# Generated by FakeRAM 2.0
VERSION 5.7 ;
BUSBITCHARS "[]" ;
PROPERTYDEFINITIONS
  MACRO width INTEGER ;
  MACRO depth INTEGER ;
  MACRO banks INTEGER ;
END PROPERTYDEFINITIONS
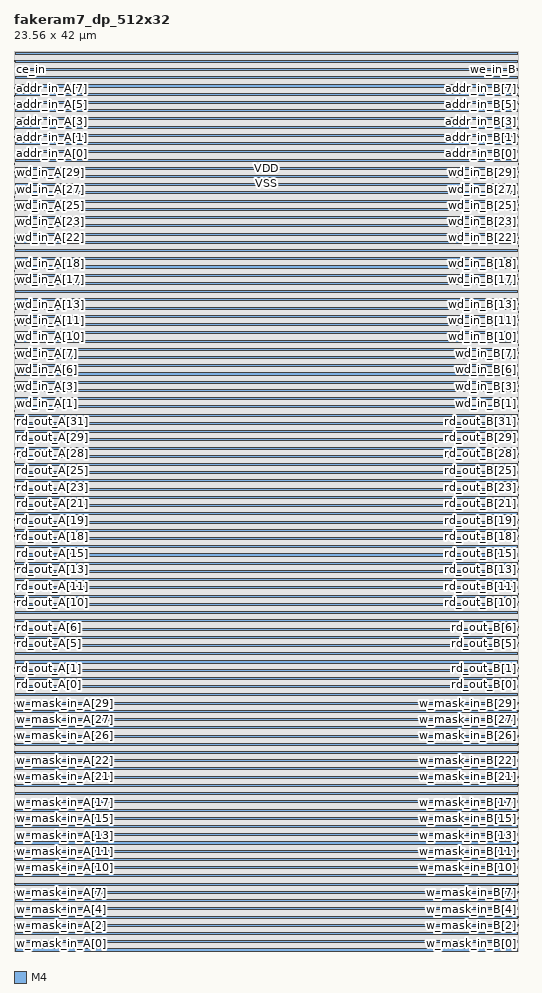
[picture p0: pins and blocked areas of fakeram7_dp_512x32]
MACRO fakeram7_dp_512x32
  PROPERTY width 32 ;
  PROPERTY depth 512 ;
  PROPERTY banks 4 ;
  FOREIGN fakeram7_dp_512x32 0 0 ;
  SYMMETRY X Y ;
  SIZE 23.560 BY 42.000 ;
  CLASS BLOCK ;
  PIN w_mask_in_A[0]
    DIRECTION INPUT ;
    USE SIGNAL ;
    SHAPE ABUTMENT ;
    PORT
      LAYER M4 ;
      RECT 0.000 0.048 0.024 0.072 ;
    END
  END w_mask_in_A[0]
  PIN w_mask_in_B[0]
    DIRECTION INPUT ;
    USE SIGNAL ;
    SHAPE ABUTMENT ;
    PORT
      LAYER M4 ;
      RECT 23.536 0.048 23.560 0.072 ;
    END
  END w_mask_in_B[0]
  PIN w_mask_in_A[1]
    DIRECTION INPUT ;
    USE SIGNAL ;
    SHAPE ABUTMENT ;
    PORT
      LAYER M4 ;
      RECT 0.000 0.432 0.024 0.456 ;
    END
  END w_mask_in_A[1]
  PIN w_mask_in_B[1]
    DIRECTION INPUT ;
    USE SIGNAL ;
    SHAPE ABUTMENT ;
    PORT
      LAYER M4 ;
      RECT 23.536 0.432 23.560 0.456 ;
    END
  END w_mask_in_B[1]
  PIN w_mask_in_A[2]
    DIRECTION INPUT ;
    USE SIGNAL ;
    SHAPE ABUTMENT ;
    PORT
      LAYER M4 ;
      RECT 0.000 0.816 0.024 0.840 ;
    END
  END w_mask_in_A[2]
  PIN w_mask_in_B[2]
    DIRECTION INPUT ;
    USE SIGNAL ;
    SHAPE ABUTMENT ;
    PORT
      LAYER M4 ;
      RECT 23.536 0.816 23.560 0.840 ;
    END
  END w_mask_in_B[2]
  PIN w_mask_in_A[3]
    DIRECTION INPUT ;
    USE SIGNAL ;
    SHAPE ABUTMENT ;
    PORT
      LAYER M4 ;
      RECT 0.000 1.200 0.024 1.224 ;
    END
  END w_mask_in_A[3]
  PIN w_mask_in_B[3]
    DIRECTION INPUT ;
    USE SIGNAL ;
    SHAPE ABUTMENT ;
    PORT
      LAYER M4 ;
      RECT 23.536 1.200 23.560 1.224 ;
    END
  END w_mask_in_B[3]
  PIN w_mask_in_A[4]
    DIRECTION INPUT ;
    USE SIGNAL ;
    SHAPE ABUTMENT ;
    PORT
      LAYER M4 ;
      RECT 0.000 1.584 0.024 1.608 ;
    END
  END w_mask_in_A[4]
  PIN w_mask_in_B[4]
    DIRECTION INPUT ;
    USE SIGNAL ;
    SHAPE ABUTMENT ;
    PORT
      LAYER M4 ;
      RECT 23.536 1.584 23.560 1.608 ;
    END
  END w_mask_in_B[4]
  PIN w_mask_in_A[5]
    DIRECTION INPUT ;
    USE SIGNAL ;
    SHAPE ABUTMENT ;
    PORT
      LAYER M4 ;
      RECT 0.000 1.968 0.024 1.992 ;
    END
  END w_mask_in_A[5]
  PIN w_mask_in_B[5]
    DIRECTION INPUT ;
    USE SIGNAL ;
    SHAPE ABUTMENT ;
    PORT
      LAYER M4 ;
      RECT 23.536 1.968 23.560 1.992 ;
    END
  END w_mask_in_B[5]
  PIN w_mask_in_A[6]
    DIRECTION INPUT ;
    USE SIGNAL ;
    SHAPE ABUTMENT ;
    PORT
      LAYER M4 ;
      RECT 0.000 2.352 0.024 2.376 ;
    END
  END w_mask_in_A[6]
  PIN w_mask_in_B[6]
    DIRECTION INPUT ;
    USE SIGNAL ;
    SHAPE ABUTMENT ;
    PORT
      LAYER M4 ;
      RECT 23.536 2.352 23.560 2.376 ;
    END
  END w_mask_in_B[6]
  PIN w_mask_in_A[7]
    DIRECTION INPUT ;
    USE SIGNAL ;
    SHAPE ABUTMENT ;
    PORT
      LAYER M4 ;
      RECT 0.000 2.736 0.024 2.760 ;
    END
  END w_mask_in_A[7]
  PIN w_mask_in_B[7]
    DIRECTION INPUT ;
    USE SIGNAL ;
    SHAPE ABUTMENT ;
    PORT
      LAYER M4 ;
      RECT 23.536 2.736 23.560 2.760 ;
    END
  END w_mask_in_B[7]
  PIN w_mask_in_A[8]
    DIRECTION INPUT ;
    USE SIGNAL ;
    SHAPE ABUTMENT ;
    PORT
      LAYER M4 ;
      RECT 0.000 3.120 0.024 3.144 ;
    END
  END w_mask_in_A[8]
  PIN w_mask_in_B[8]
    DIRECTION INPUT ;
    USE SIGNAL ;
    SHAPE ABUTMENT ;
    PORT
      LAYER M4 ;
      RECT 23.536 3.120 23.560 3.144 ;
    END
  END w_mask_in_B[8]
  PIN w_mask_in_A[9]
    DIRECTION INPUT ;
    USE SIGNAL ;
    SHAPE ABUTMENT ;
    PORT
      LAYER M4 ;
      RECT 0.000 3.504 0.024 3.528 ;
    END
  END w_mask_in_A[9]
  PIN w_mask_in_B[9]
    DIRECTION INPUT ;
    USE SIGNAL ;
    SHAPE ABUTMENT ;
    PORT
      LAYER M4 ;
      RECT 23.536 3.504 23.560 3.528 ;
    END
  END w_mask_in_B[9]
  PIN w_mask_in_A[10]
    DIRECTION INPUT ;
    USE SIGNAL ;
    SHAPE ABUTMENT ;
    PORT
      LAYER M4 ;
      RECT 0.000 3.888 0.024 3.912 ;
    END
  END w_mask_in_A[10]
  PIN w_mask_in_B[10]
    DIRECTION INPUT ;
    USE SIGNAL ;
    SHAPE ABUTMENT ;
    PORT
      LAYER M4 ;
      RECT 23.536 3.888 23.560 3.912 ;
    END
  END w_mask_in_B[10]
  PIN w_mask_in_A[11]
    DIRECTION INPUT ;
    USE SIGNAL ;
    SHAPE ABUTMENT ;
    PORT
      LAYER M4 ;
      RECT 0.000 4.272 0.024 4.296 ;
    END
  END w_mask_in_A[11]
  PIN w_mask_in_B[11]
    DIRECTION INPUT ;
    USE SIGNAL ;
    SHAPE ABUTMENT ;
    PORT
      LAYER M4 ;
      RECT 23.536 4.272 23.560 4.296 ;
    END
  END w_mask_in_B[11]
  PIN w_mask_in_A[12]
    DIRECTION INPUT ;
    USE SIGNAL ;
    SHAPE ABUTMENT ;
    PORT
      LAYER M4 ;
      RECT 0.000 4.656 0.024 4.680 ;
    END
  END w_mask_in_A[12]
  PIN w_mask_in_B[12]
    DIRECTION INPUT ;
    USE SIGNAL ;
    SHAPE ABUTMENT ;
    PORT
      LAYER M4 ;
      RECT 23.536 4.656 23.560 4.680 ;
    END
  END w_mask_in_B[12]
  PIN w_mask_in_A[13]
    DIRECTION INPUT ;
    USE SIGNAL ;
    SHAPE ABUTMENT ;
    PORT
      LAYER M4 ;
      RECT 0.000 5.040 0.024 5.064 ;
    END
  END w_mask_in_A[13]
  PIN w_mask_in_B[13]
    DIRECTION INPUT ;
    USE SIGNAL ;
    SHAPE ABUTMENT ;
    PORT
      LAYER M4 ;
      RECT 23.536 5.040 23.560 5.064 ;
    END
  END w_mask_in_B[13]
  PIN w_mask_in_A[14]
    DIRECTION INPUT ;
    USE SIGNAL ;
    SHAPE ABUTMENT ;
    PORT
      LAYER M4 ;
      RECT 0.000 5.424 0.024 5.448 ;
    END
  END w_mask_in_A[14]
  PIN w_mask_in_B[14]
    DIRECTION INPUT ;
    USE SIGNAL ;
    SHAPE ABUTMENT ;
    PORT
      LAYER M4 ;
      RECT 23.536 5.424 23.560 5.448 ;
    END
  END w_mask_in_B[14]
  PIN w_mask_in_A[15]
    DIRECTION INPUT ;
    USE SIGNAL ;
    SHAPE ABUTMENT ;
    PORT
      LAYER M4 ;
      RECT 0.000 5.808 0.024 5.832 ;
    END
  END w_mask_in_A[15]
  PIN w_mask_in_B[15]
    DIRECTION INPUT ;
    USE SIGNAL ;
    SHAPE ABUTMENT ;
    PORT
      LAYER M4 ;
      RECT 23.536 5.808 23.560 5.832 ;
    END
  END w_mask_in_B[15]
  PIN w_mask_in_A[16]
    DIRECTION INPUT ;
    USE SIGNAL ;
    SHAPE ABUTMENT ;
    PORT
      LAYER M4 ;
      RECT 0.000 6.192 0.024 6.216 ;
    END
  END w_mask_in_A[16]
  PIN w_mask_in_B[16]
    DIRECTION INPUT ;
    USE SIGNAL ;
    SHAPE ABUTMENT ;
    PORT
      LAYER M4 ;
      RECT 23.536 6.192 23.560 6.216 ;
    END
  END w_mask_in_B[16]
  PIN w_mask_in_A[17]
    DIRECTION INPUT ;
    USE SIGNAL ;
    SHAPE ABUTMENT ;
    PORT
      LAYER M4 ;
      RECT 0.000 6.576 0.024 6.600 ;
    END
  END w_mask_in_A[17]
  PIN w_mask_in_B[17]
    DIRECTION INPUT ;
    USE SIGNAL ;
    SHAPE ABUTMENT ;
    PORT
      LAYER M4 ;
      RECT 23.536 6.576 23.560 6.600 ;
    END
  END w_mask_in_B[17]
  PIN w_mask_in_A[18]
    DIRECTION INPUT ;
    USE SIGNAL ;
    SHAPE ABUTMENT ;
    PORT
      LAYER M4 ;
      RECT 0.000 6.960 0.024 6.984 ;
    END
  END w_mask_in_A[18]
  PIN w_mask_in_B[18]
    DIRECTION INPUT ;
    USE SIGNAL ;
    SHAPE ABUTMENT ;
    PORT
      LAYER M4 ;
      RECT 23.536 6.960 23.560 6.984 ;
    END
  END w_mask_in_B[18]
  PIN w_mask_in_A[19]
    DIRECTION INPUT ;
    USE SIGNAL ;
    SHAPE ABUTMENT ;
    PORT
      LAYER M4 ;
      RECT 0.000 7.344 0.024 7.368 ;
    END
  END w_mask_in_A[19]
  PIN w_mask_in_B[19]
    DIRECTION INPUT ;
    USE SIGNAL ;
    SHAPE ABUTMENT ;
    PORT
      LAYER M4 ;
      RECT 23.536 7.344 23.560 7.368 ;
    END
  END w_mask_in_B[19]
  PIN w_mask_in_A[20]
    DIRECTION INPUT ;
    USE SIGNAL ;
    SHAPE ABUTMENT ;
    PORT
      LAYER M4 ;
      RECT 0.000 7.728 0.024 7.752 ;
    END
  END w_mask_in_A[20]
  PIN w_mask_in_B[20]
    DIRECTION INPUT ;
    USE SIGNAL ;
    SHAPE ABUTMENT ;
    PORT
      LAYER M4 ;
      RECT 23.536 7.728 23.560 7.752 ;
    END
  END w_mask_in_B[20]
  PIN w_mask_in_A[21]
    DIRECTION INPUT ;
    USE SIGNAL ;
    SHAPE ABUTMENT ;
    PORT
      LAYER M4 ;
      RECT 0.000 8.112 0.024 8.136 ;
    END
  END w_mask_in_A[21]
  PIN w_mask_in_B[21]
    DIRECTION INPUT ;
    USE SIGNAL ;
    SHAPE ABUTMENT ;
    PORT
      LAYER M4 ;
      RECT 23.536 8.112 23.560 8.136 ;
    END
  END w_mask_in_B[21]
  PIN w_mask_in_A[22]
    DIRECTION INPUT ;
    USE SIGNAL ;
    SHAPE ABUTMENT ;
    PORT
      LAYER M4 ;
      RECT 0.000 8.496 0.024 8.520 ;
    END
  END w_mask_in_A[22]
  PIN w_mask_in_B[22]
    DIRECTION INPUT ;
    USE SIGNAL ;
    SHAPE ABUTMENT ;
    PORT
      LAYER M4 ;
      RECT 23.536 8.496 23.560 8.520 ;
    END
  END w_mask_in_B[22]
  PIN w_mask_in_A[23]
    DIRECTION INPUT ;
    USE SIGNAL ;
    SHAPE ABUTMENT ;
    PORT
      LAYER M4 ;
      RECT 0.000 8.880 0.024 8.904 ;
    END
  END w_mask_in_A[23]
  PIN w_mask_in_B[23]
    DIRECTION INPUT ;
    USE SIGNAL ;
    SHAPE ABUTMENT ;
    PORT
      LAYER M4 ;
      RECT 23.536 8.880 23.560 8.904 ;
    END
  END w_mask_in_B[23]
  PIN w_mask_in_A[24]
    DIRECTION INPUT ;
    USE SIGNAL ;
    SHAPE ABUTMENT ;
    PORT
      LAYER M4 ;
      RECT 0.000 9.264 0.024 9.288 ;
    END
  END w_mask_in_A[24]
  PIN w_mask_in_B[24]
    DIRECTION INPUT ;
    USE SIGNAL ;
    SHAPE ABUTMENT ;
    PORT
      LAYER M4 ;
      RECT 23.536 9.264 23.560 9.288 ;
    END
  END w_mask_in_B[24]
  PIN w_mask_in_A[25]
    DIRECTION INPUT ;
    USE SIGNAL ;
    SHAPE ABUTMENT ;
    PORT
      LAYER M4 ;
      RECT 0.000 9.648 0.024 9.672 ;
    END
  END w_mask_in_A[25]
  PIN w_mask_in_B[25]
    DIRECTION INPUT ;
    USE SIGNAL ;
    SHAPE ABUTMENT ;
    PORT
      LAYER M4 ;
      RECT 23.536 9.648 23.560 9.672 ;
    END
  END w_mask_in_B[25]
  PIN w_mask_in_A[26]
    DIRECTION INPUT ;
    USE SIGNAL ;
    SHAPE ABUTMENT ;
    PORT
      LAYER M4 ;
      RECT 0.000 10.032 0.024 10.056 ;
    END
  END w_mask_in_A[26]
  PIN w_mask_in_B[26]
    DIRECTION INPUT ;
    USE SIGNAL ;
    SHAPE ABUTMENT ;
    PORT
      LAYER M4 ;
      RECT 23.536 10.032 23.560 10.056 ;
    END
  END w_mask_in_B[26]
  PIN w_mask_in_A[27]
    DIRECTION INPUT ;
    USE SIGNAL ;
    SHAPE ABUTMENT ;
    PORT
      LAYER M4 ;
      RECT 0.000 10.416 0.024 10.440 ;
    END
  END w_mask_in_A[27]
  PIN w_mask_in_B[27]
    DIRECTION INPUT ;
    USE SIGNAL ;
    SHAPE ABUTMENT ;
    PORT
      LAYER M4 ;
      RECT 23.536 10.416 23.560 10.440 ;
    END
  END w_mask_in_B[27]
  PIN w_mask_in_A[28]
    DIRECTION INPUT ;
    USE SIGNAL ;
    SHAPE ABUTMENT ;
    PORT
      LAYER M4 ;
      RECT 0.000 10.800 0.024 10.824 ;
    END
  END w_mask_in_A[28]
  PIN w_mask_in_B[28]
    DIRECTION INPUT ;
    USE SIGNAL ;
    SHAPE ABUTMENT ;
    PORT
      LAYER M4 ;
      RECT 23.536 10.800 23.560 10.824 ;
    END
  END w_mask_in_B[28]
  PIN w_mask_in_A[29]
    DIRECTION INPUT ;
    USE SIGNAL ;
    SHAPE ABUTMENT ;
    PORT
      LAYER M4 ;
      RECT 0.000 11.184 0.024 11.208 ;
    END
  END w_mask_in_A[29]
  PIN w_mask_in_B[29]
    DIRECTION INPUT ;
    USE SIGNAL ;
    SHAPE ABUTMENT ;
    PORT
      LAYER M4 ;
      RECT 23.536 11.184 23.560 11.208 ;
    END
  END w_mask_in_B[29]
  PIN w_mask_in_A[30]
    DIRECTION INPUT ;
    USE SIGNAL ;
    SHAPE ABUTMENT ;
    PORT
      LAYER M4 ;
      RECT 0.000 11.568 0.024 11.592 ;
    END
  END w_mask_in_A[30]
  PIN w_mask_in_B[30]
    DIRECTION INPUT ;
    USE SIGNAL ;
    SHAPE ABUTMENT ;
    PORT
      LAYER M4 ;
      RECT 23.536 11.568 23.560 11.592 ;
    END
  END w_mask_in_B[30]
  PIN w_mask_in_A[31]
    DIRECTION INPUT ;
    USE SIGNAL ;
    SHAPE ABUTMENT ;
    PORT
      LAYER M4 ;
      RECT 0.000 11.952 0.024 11.976 ;
    END
  END w_mask_in_A[31]
  PIN w_mask_in_B[31]
    DIRECTION INPUT ;
    USE SIGNAL ;
    SHAPE ABUTMENT ;
    PORT
      LAYER M4 ;
      RECT 23.536 11.952 23.560 11.976 ;
    END
  END w_mask_in_B[31]
  PIN rd_out_A[0]
    DIRECTION OUTPUT ;
    USE SIGNAL ;
    SHAPE ABUTMENT ;
    PORT
      LAYER M4 ;
      RECT 0.000 12.432 0.024 12.456 ;
    END
  END rd_out_A[0]
  PIN rd_out_B[0]
    DIRECTION OUTPUT ;
    USE SIGNAL ;
    SHAPE ABUTMENT ;
    PORT
      LAYER M4 ;
      RECT 23.536 12.432 23.560 12.456 ;
    END
  END rd_out_B[0]
  PIN rd_out_A[1]
    DIRECTION OUTPUT ;
    USE SIGNAL ;
    SHAPE ABUTMENT ;
    PORT
      LAYER M4 ;
      RECT 0.000 12.816 0.024 12.840 ;
    END
  END rd_out_A[1]
  PIN rd_out_B[1]
    DIRECTION OUTPUT ;
    USE SIGNAL ;
    SHAPE ABUTMENT ;
    PORT
      LAYER M4 ;
      RECT 23.536 12.816 23.560 12.840 ;
    END
  END rd_out_B[1]
  PIN rd_out_A[2]
    DIRECTION OUTPUT ;
    USE SIGNAL ;
    SHAPE ABUTMENT ;
    PORT
      LAYER M4 ;
      RECT 0.000 13.200 0.024 13.224 ;
    END
  END rd_out_A[2]
  PIN rd_out_B[2]
    DIRECTION OUTPUT ;
    USE SIGNAL ;
    SHAPE ABUTMENT ;
    PORT
      LAYER M4 ;
      RECT 23.536 13.200 23.560 13.224 ;
    END
  END rd_out_B[2]
  PIN rd_out_A[3]
    DIRECTION OUTPUT ;
    USE SIGNAL ;
    SHAPE ABUTMENT ;
    PORT
      LAYER M4 ;
      RECT 0.000 13.584 0.024 13.608 ;
    END
  END rd_out_A[3]
  PIN rd_out_B[3]
    DIRECTION OUTPUT ;
    USE SIGNAL ;
    SHAPE ABUTMENT ;
    PORT
      LAYER M4 ;
      RECT 23.536 13.584 23.560 13.608 ;
    END
  END rd_out_B[3]
  PIN rd_out_A[4]
    DIRECTION OUTPUT ;
    USE SIGNAL ;
    SHAPE ABUTMENT ;
    PORT
      LAYER M4 ;
      RECT 0.000 13.968 0.024 13.992 ;
    END
  END rd_out_A[4]
  PIN rd_out_B[4]
    DIRECTION OUTPUT ;
    USE SIGNAL ;
    SHAPE ABUTMENT ;
    PORT
      LAYER M4 ;
      RECT 23.536 13.968 23.560 13.992 ;
    END
  END rd_out_B[4]
  PIN rd_out_A[5]
    DIRECTION OUTPUT ;
    USE SIGNAL ;
    SHAPE ABUTMENT ;
    PORT
      LAYER M4 ;
      RECT 0.000 14.352 0.024 14.376 ;
    END
  END rd_out_A[5]
  PIN rd_out_B[5]
    DIRECTION OUTPUT ;
    USE SIGNAL ;
    SHAPE ABUTMENT ;
    PORT
      LAYER M4 ;
      RECT 23.536 14.352 23.560 14.376 ;
    END
  END rd_out_B[5]
  PIN rd_out_A[6]
    DIRECTION OUTPUT ;
    USE SIGNAL ;
    SHAPE ABUTMENT ;
    PORT
      LAYER M4 ;
      RECT 0.000 14.736 0.024 14.760 ;
    END
  END rd_out_A[6]
  PIN rd_out_B[6]
    DIRECTION OUTPUT ;
    USE SIGNAL ;
    SHAPE ABUTMENT ;
    PORT
      LAYER M4 ;
      RECT 23.536 14.736 23.560 14.760 ;
    END
  END rd_out_B[6]
  PIN rd_out_A[7]
    DIRECTION OUTPUT ;
    USE SIGNAL ;
    SHAPE ABUTMENT ;
    PORT
      LAYER M4 ;
      RECT 0.000 15.120 0.024 15.144 ;
    END
  END rd_out_A[7]
  PIN rd_out_B[7]
    DIRECTION OUTPUT ;
    USE SIGNAL ;
    SHAPE ABUTMENT ;
    PORT
      LAYER M4 ;
      RECT 23.536 15.120 23.560 15.144 ;
    END
  END rd_out_B[7]
  PIN rd_out_A[8]
    DIRECTION OUTPUT ;
    USE SIGNAL ;
    SHAPE ABUTMENT ;
    PORT
      LAYER M4 ;
      RECT 0.000 15.504 0.024 15.528 ;
    END
  END rd_out_A[8]
  PIN rd_out_B[8]
    DIRECTION OUTPUT ;
    USE SIGNAL ;
    SHAPE ABUTMENT ;
    PORT
      LAYER M4 ;
      RECT 23.536 15.504 23.560 15.528 ;
    END
  END rd_out_B[8]
  PIN rd_out_A[9]
    DIRECTION OUTPUT ;
    USE SIGNAL ;
    SHAPE ABUTMENT ;
    PORT
      LAYER M4 ;
      RECT 0.000 15.888 0.024 15.912 ;
    END
  END rd_out_A[9]
  PIN rd_out_B[9]
    DIRECTION OUTPUT ;
    USE SIGNAL ;
    SHAPE ABUTMENT ;
    PORT
      LAYER M4 ;
      RECT 23.536 15.888 23.560 15.912 ;
    END
  END rd_out_B[9]
  PIN rd_out_A[10]
    DIRECTION OUTPUT ;
    USE SIGNAL ;
    SHAPE ABUTMENT ;
    PORT
      LAYER M4 ;
      RECT 0.000 16.272 0.024 16.296 ;
    END
  END rd_out_A[10]
  PIN rd_out_B[10]
    DIRECTION OUTPUT ;
    USE SIGNAL ;
    SHAPE ABUTMENT ;
    PORT
      LAYER M4 ;
      RECT 23.536 16.272 23.560 16.296 ;
    END
  END rd_out_B[10]
  PIN rd_out_A[11]
    DIRECTION OUTPUT ;
    USE SIGNAL ;
    SHAPE ABUTMENT ;
    PORT
      LAYER M4 ;
      RECT 0.000 16.656 0.024 16.680 ;
    END
  END rd_out_A[11]
  PIN rd_out_B[11]
    DIRECTION OUTPUT ;
    USE SIGNAL ;
    SHAPE ABUTMENT ;
    PORT
      LAYER M4 ;
      RECT 23.536 16.656 23.560 16.680 ;
    END
  END rd_out_B[11]
  PIN rd_out_A[12]
    DIRECTION OUTPUT ;
    USE SIGNAL ;
    SHAPE ABUTMENT ;
    PORT
      LAYER M4 ;
      RECT 0.000 17.040 0.024 17.064 ;
    END
  END rd_out_A[12]
  PIN rd_out_B[12]
    DIRECTION OUTPUT ;
    USE SIGNAL ;
    SHAPE ABUTMENT ;
    PORT
      LAYER M4 ;
      RECT 23.536 17.040 23.560 17.064 ;
    END
  END rd_out_B[12]
  PIN rd_out_A[13]
    DIRECTION OUTPUT ;
    USE SIGNAL ;
    SHAPE ABUTMENT ;
    PORT
      LAYER M4 ;
      RECT 0.000 17.424 0.024 17.448 ;
    END
  END rd_out_A[13]
  PIN rd_out_B[13]
    DIRECTION OUTPUT ;
    USE SIGNAL ;
    SHAPE ABUTMENT ;
    PORT
      LAYER M4 ;
      RECT 23.536 17.424 23.560 17.448 ;
    END
  END rd_out_B[13]
  PIN rd_out_A[14]
    DIRECTION OUTPUT ;
    USE SIGNAL ;
    SHAPE ABUTMENT ;
    PORT
      LAYER M4 ;
      RECT 0.000 17.808 0.024 17.832 ;
    END
  END rd_out_A[14]
  PIN rd_out_B[14]
    DIRECTION OUTPUT ;
    USE SIGNAL ;
    SHAPE ABUTMENT ;
    PORT
      LAYER M4 ;
      RECT 23.536 17.808 23.560 17.832 ;
    END
  END rd_out_B[14]
  PIN rd_out_A[15]
    DIRECTION OUTPUT ;
    USE SIGNAL ;
    SHAPE ABUTMENT ;
    PORT
      LAYER M4 ;
      RECT 0.000 18.192 0.024 18.216 ;
    END
  END rd_out_A[15]
  PIN rd_out_B[15]
    DIRECTION OUTPUT ;
    USE SIGNAL ;
    SHAPE ABUTMENT ;
    PORT
      LAYER M4 ;
      RECT 23.536 18.192 23.560 18.216 ;
    END
  END rd_out_B[15]
  PIN rd_out_A[16]
    DIRECTION OUTPUT ;
    USE SIGNAL ;
    SHAPE ABUTMENT ;
    PORT
      LAYER M4 ;
      RECT 0.000 18.576 0.024 18.600 ;
    END
  END rd_out_A[16]
  PIN rd_out_B[16]
    DIRECTION OUTPUT ;
    USE SIGNAL ;
    SHAPE ABUTMENT ;
    PORT
      LAYER M4 ;
      RECT 23.536 18.576 23.560 18.600 ;
    END
  END rd_out_B[16]
  PIN rd_out_A[17]
    DIRECTION OUTPUT ;
    USE SIGNAL ;
    SHAPE ABUTMENT ;
    PORT
      LAYER M4 ;
      RECT 0.000 18.960 0.024 18.984 ;
    END
  END rd_out_A[17]
  PIN rd_out_B[17]
    DIRECTION OUTPUT ;
    USE SIGNAL ;
    SHAPE ABUTMENT ;
    PORT
      LAYER M4 ;
      RECT 23.536 18.960 23.560 18.984 ;
    END
  END rd_out_B[17]
  PIN rd_out_A[18]
    DIRECTION OUTPUT ;
    USE SIGNAL ;
    SHAPE ABUTMENT ;
    PORT
      LAYER M4 ;
      RECT 0.000 19.344 0.024 19.368 ;
    END
  END rd_out_A[18]
  PIN rd_out_B[18]
    DIRECTION OUTPUT ;
    USE SIGNAL ;
    SHAPE ABUTMENT ;
    PORT
      LAYER M4 ;
      RECT 23.536 19.344 23.560 19.368 ;
    END
  END rd_out_B[18]
  PIN rd_out_A[19]
    DIRECTION OUTPUT ;
    USE SIGNAL ;
    SHAPE ABUTMENT ;
    PORT
      LAYER M4 ;
      RECT 0.000 19.728 0.024 19.752 ;
    END
  END rd_out_A[19]
  PIN rd_out_B[19]
    DIRECTION OUTPUT ;
    USE SIGNAL ;
    SHAPE ABUTMENT ;
    PORT
      LAYER M4 ;
      RECT 23.536 19.728 23.560 19.752 ;
    END
  END rd_out_B[19]
  PIN rd_out_A[20]
    DIRECTION OUTPUT ;
    USE SIGNAL ;
    SHAPE ABUTMENT ;
    PORT
      LAYER M4 ;
      RECT 0.000 20.112 0.024 20.136 ;
    END
  END rd_out_A[20]
  PIN rd_out_B[20]
    DIRECTION OUTPUT ;
    USE SIGNAL ;
    SHAPE ABUTMENT ;
    PORT
      LAYER M4 ;
      RECT 23.536 20.112 23.560 20.136 ;
    END
  END rd_out_B[20]
  PIN rd_out_A[21]
    DIRECTION OUTPUT ;
    USE SIGNAL ;
    SHAPE ABUTMENT ;
    PORT
      LAYER M4 ;
      RECT 0.000 20.496 0.024 20.520 ;
    END
  END rd_out_A[21]
  PIN rd_out_B[21]
    DIRECTION OUTPUT ;
    USE SIGNAL ;
    SHAPE ABUTMENT ;
    PORT
      LAYER M4 ;
      RECT 23.536 20.496 23.560 20.520 ;
    END
  END rd_out_B[21]
  PIN rd_out_A[22]
    DIRECTION OUTPUT ;
    USE SIGNAL ;
    SHAPE ABUTMENT ;
    PORT
      LAYER M4 ;
      RECT 0.000 20.880 0.024 20.904 ;
    END
  END rd_out_A[22]
  PIN rd_out_B[22]
    DIRECTION OUTPUT ;
    USE SIGNAL ;
    SHAPE ABUTMENT ;
    PORT
      LAYER M4 ;
      RECT 23.536 20.880 23.560 20.904 ;
    END
  END rd_out_B[22]
  PIN rd_out_A[23]
    DIRECTION OUTPUT ;
    USE SIGNAL ;
    SHAPE ABUTMENT ;
    PORT
      LAYER M4 ;
      RECT 0.000 21.264 0.024 21.288 ;
    END
  END rd_out_A[23]
  PIN rd_out_B[23]
    DIRECTION OUTPUT ;
    USE SIGNAL ;
    SHAPE ABUTMENT ;
    PORT
      LAYER M4 ;
      RECT 23.536 21.264 23.560 21.288 ;
    END
  END rd_out_B[23]
  PIN rd_out_A[24]
    DIRECTION OUTPUT ;
    USE SIGNAL ;
    SHAPE ABUTMENT ;
    PORT
      LAYER M4 ;
      RECT 0.000 21.648 0.024 21.672 ;
    END
  END rd_out_A[24]
  PIN rd_out_B[24]
    DIRECTION OUTPUT ;
    USE SIGNAL ;
    SHAPE ABUTMENT ;
    PORT
      LAYER M4 ;
      RECT 23.536 21.648 23.560 21.672 ;
    END
  END rd_out_B[24]
  PIN rd_out_A[25]
    DIRECTION OUTPUT ;
    USE SIGNAL ;
    SHAPE ABUTMENT ;
    PORT
      LAYER M4 ;
      RECT 0.000 22.032 0.024 22.056 ;
    END
  END rd_out_A[25]
  PIN rd_out_B[25]
    DIRECTION OUTPUT ;
    USE SIGNAL ;
    SHAPE ABUTMENT ;
    PORT
      LAYER M4 ;
      RECT 23.536 22.032 23.560 22.056 ;
    END
  END rd_out_B[25]
  PIN rd_out_A[26]
    DIRECTION OUTPUT ;
    USE SIGNAL ;
    SHAPE ABUTMENT ;
    PORT
      LAYER M4 ;
      RECT 0.000 22.416 0.024 22.440 ;
    END
  END rd_out_A[26]
  PIN rd_out_B[26]
    DIRECTION OUTPUT ;
    USE SIGNAL ;
    SHAPE ABUTMENT ;
    PORT
      LAYER M4 ;
      RECT 23.536 22.416 23.560 22.440 ;
    END
  END rd_out_B[26]
  PIN rd_out_A[27]
    DIRECTION OUTPUT ;
    USE SIGNAL ;
    SHAPE ABUTMENT ;
    PORT
      LAYER M4 ;
      RECT 0.000 22.800 0.024 22.824 ;
    END
  END rd_out_A[27]
  PIN rd_out_B[27]
    DIRECTION OUTPUT ;
    USE SIGNAL ;
    SHAPE ABUTMENT ;
    PORT
      LAYER M4 ;
      RECT 23.536 22.800 23.560 22.824 ;
    END
  END rd_out_B[27]
  PIN rd_out_A[28]
    DIRECTION OUTPUT ;
    USE SIGNAL ;
    SHAPE ABUTMENT ;
    PORT
      LAYER M4 ;
      RECT 0.000 23.184 0.024 23.208 ;
    END
  END rd_out_A[28]
  PIN rd_out_B[28]
    DIRECTION OUTPUT ;
    USE SIGNAL ;
    SHAPE ABUTMENT ;
    PORT
      LAYER M4 ;
      RECT 23.536 23.184 23.560 23.208 ;
    END
  END rd_out_B[28]
  PIN rd_out_A[29]
    DIRECTION OUTPUT ;
    USE SIGNAL ;
    SHAPE ABUTMENT ;
    PORT
      LAYER M4 ;
      RECT 0.000 23.568 0.024 23.592 ;
    END
  END rd_out_A[29]
  PIN rd_out_B[29]
    DIRECTION OUTPUT ;
    USE SIGNAL ;
    SHAPE ABUTMENT ;
    PORT
      LAYER M4 ;
      RECT 23.536 23.568 23.560 23.592 ;
    END
  END rd_out_B[29]
  PIN rd_out_A[30]
    DIRECTION OUTPUT ;
    USE SIGNAL ;
    SHAPE ABUTMENT ;
    PORT
      LAYER M4 ;
      RECT 0.000 23.952 0.024 23.976 ;
    END
  END rd_out_A[30]
  PIN rd_out_B[30]
    DIRECTION OUTPUT ;
    USE SIGNAL ;
    SHAPE ABUTMENT ;
    PORT
      LAYER M4 ;
      RECT 23.536 23.952 23.560 23.976 ;
    END
  END rd_out_B[30]
  PIN rd_out_A[31]
    DIRECTION OUTPUT ;
    USE SIGNAL ;
    SHAPE ABUTMENT ;
    PORT
      LAYER M4 ;
      RECT 0.000 24.336 0.024 24.360 ;
    END
  END rd_out_A[31]
  PIN rd_out_B[31]
    DIRECTION OUTPUT ;
    USE SIGNAL ;
    SHAPE ABUTMENT ;
    PORT
      LAYER M4 ;
      RECT 23.536 24.336 23.560 24.360 ;
    END
  END rd_out_B[31]
  PIN wd_in_A[0]
    DIRECTION INPUT ;
    USE SIGNAL ;
    SHAPE ABUTMENT ;
    PORT
      LAYER M4 ;
      RECT 0.000 24.816 0.024 24.840 ;
    END
  END wd_in_A[0]
  PIN wd_in_B[0]
    DIRECTION INPUT ;
    USE SIGNAL ;
    SHAPE ABUTMENT ;
    PORT
      LAYER M4 ;
      RECT 23.536 24.816 23.560 24.840 ;
    END
  END wd_in_B[0]
  PIN wd_in_A[1]
    DIRECTION INPUT ;
    USE SIGNAL ;
    SHAPE ABUTMENT ;
    PORT
      LAYER M4 ;
      RECT 0.000 25.200 0.024 25.224 ;
    END
  END wd_in_A[1]
  PIN wd_in_B[1]
    DIRECTION INPUT ;
    USE SIGNAL ;
    SHAPE ABUTMENT ;
    PORT
      LAYER M4 ;
      RECT 23.536 25.200 23.560 25.224 ;
    END
  END wd_in_B[1]
  PIN wd_in_A[2]
    DIRECTION INPUT ;
    USE SIGNAL ;
    SHAPE ABUTMENT ;
    PORT
      LAYER M4 ;
      RECT 0.000 25.584 0.024 25.608 ;
    END
  END wd_in_A[2]
  PIN wd_in_B[2]
    DIRECTION INPUT ;
    USE SIGNAL ;
    SHAPE ABUTMENT ;
    PORT
      LAYER M4 ;
      RECT 23.536 25.584 23.560 25.608 ;
    END
  END wd_in_B[2]
  PIN wd_in_A[3]
    DIRECTION INPUT ;
    USE SIGNAL ;
    SHAPE ABUTMENT ;
    PORT
      LAYER M4 ;
      RECT 0.000 25.968 0.024 25.992 ;
    END
  END wd_in_A[3]
  PIN wd_in_B[3]
    DIRECTION INPUT ;
    USE SIGNAL ;
    SHAPE ABUTMENT ;
    PORT
      LAYER M4 ;
      RECT 23.536 25.968 23.560 25.992 ;
    END
  END wd_in_B[3]
  PIN wd_in_A[4]
    DIRECTION INPUT ;
    USE SIGNAL ;
    SHAPE ABUTMENT ;
    PORT
      LAYER M4 ;
      RECT 0.000 26.352 0.024 26.376 ;
    END
  END wd_in_A[4]
  PIN wd_in_B[4]
    DIRECTION INPUT ;
    USE SIGNAL ;
    SHAPE ABUTMENT ;
    PORT
      LAYER M4 ;
      RECT 23.536 26.352 23.560 26.376 ;
    END
  END wd_in_B[4]
  PIN wd_in_A[5]
    DIRECTION INPUT ;
    USE SIGNAL ;
    SHAPE ABUTMENT ;
    PORT
      LAYER M4 ;
      RECT 0.000 26.736 0.024 26.760 ;
    END
  END wd_in_A[5]
  PIN wd_in_B[5]
    DIRECTION INPUT ;
    USE SIGNAL ;
    SHAPE ABUTMENT ;
    PORT
      LAYER M4 ;
      RECT 23.536 26.736 23.560 26.760 ;
    END
  END wd_in_B[5]
  PIN wd_in_A[6]
    DIRECTION INPUT ;
    USE SIGNAL ;
    SHAPE ABUTMENT ;
    PORT
      LAYER M4 ;
      RECT 0.000 27.120 0.024 27.144 ;
    END
  END wd_in_A[6]
  PIN wd_in_B[6]
    DIRECTION INPUT ;
    USE SIGNAL ;
    SHAPE ABUTMENT ;
    PORT
      LAYER M4 ;
      RECT 23.536 27.120 23.560 27.144 ;
    END
  END wd_in_B[6]
  PIN wd_in_A[7]
    DIRECTION INPUT ;
    USE SIGNAL ;
    SHAPE ABUTMENT ;
    PORT
      LAYER M4 ;
      RECT 0.000 27.504 0.024 27.528 ;
    END
  END wd_in_A[7]
  PIN wd_in_B[7]
    DIRECTION INPUT ;
    USE SIGNAL ;
    SHAPE ABUTMENT ;
    PORT
      LAYER M4 ;
      RECT 23.536 27.504 23.560 27.528 ;
    END
  END wd_in_B[7]
  PIN wd_in_A[8]
    DIRECTION INPUT ;
    USE SIGNAL ;
    SHAPE ABUTMENT ;
    PORT
      LAYER M4 ;
      RECT 0.000 27.888 0.024 27.912 ;
    END
  END wd_in_A[8]
  PIN wd_in_B[8]
    DIRECTION INPUT ;
    USE SIGNAL ;
    SHAPE ABUTMENT ;
    PORT
      LAYER M4 ;
      RECT 23.536 27.888 23.560 27.912 ;
    END
  END wd_in_B[8]
  PIN wd_in_A[9]
    DIRECTION INPUT ;
    USE SIGNAL ;
    SHAPE ABUTMENT ;
    PORT
      LAYER M4 ;
      RECT 0.000 28.272 0.024 28.296 ;
    END
  END wd_in_A[9]
  PIN wd_in_B[9]
    DIRECTION INPUT ;
    USE SIGNAL ;
    SHAPE ABUTMENT ;
    PORT
      LAYER M4 ;
      RECT 23.536 28.272 23.560 28.296 ;
    END
  END wd_in_B[9]
  PIN wd_in_A[10]
    DIRECTION INPUT ;
    USE SIGNAL ;
    SHAPE ABUTMENT ;
    PORT
      LAYER M4 ;
      RECT 0.000 28.656 0.024 28.680 ;
    END
  END wd_in_A[10]
  PIN wd_in_B[10]
    DIRECTION INPUT ;
    USE SIGNAL ;
    SHAPE ABUTMENT ;
    PORT
      LAYER M4 ;
      RECT 23.536 28.656 23.560 28.680 ;
    END
  END wd_in_B[10]
  PIN wd_in_A[11]
    DIRECTION INPUT ;
    USE SIGNAL ;
    SHAPE ABUTMENT ;
    PORT
      LAYER M4 ;
      RECT 0.000 29.040 0.024 29.064 ;
    END
  END wd_in_A[11]
  PIN wd_in_B[11]
    DIRECTION INPUT ;
    USE SIGNAL ;
    SHAPE ABUTMENT ;
    PORT
      LAYER M4 ;
      RECT 23.536 29.040 23.560 29.064 ;
    END
  END wd_in_B[11]
  PIN wd_in_A[12]
    DIRECTION INPUT ;
    USE SIGNAL ;
    SHAPE ABUTMENT ;
    PORT
      LAYER M4 ;
      RECT 0.000 29.424 0.024 29.448 ;
    END
  END wd_in_A[12]
  PIN wd_in_B[12]
    DIRECTION INPUT ;
    USE SIGNAL ;
    SHAPE ABUTMENT ;
    PORT
      LAYER M4 ;
      RECT 23.536 29.424 23.560 29.448 ;
    END
  END wd_in_B[12]
  PIN wd_in_A[13]
    DIRECTION INPUT ;
    USE SIGNAL ;
    SHAPE ABUTMENT ;
    PORT
      LAYER M4 ;
      RECT 0.000 29.808 0.024 29.832 ;
    END
  END wd_in_A[13]
  PIN wd_in_B[13]
    DIRECTION INPUT ;
    USE SIGNAL ;
    SHAPE ABUTMENT ;
    PORT
      LAYER M4 ;
      RECT 23.536 29.808 23.560 29.832 ;
    END
  END wd_in_B[13]
  PIN wd_in_A[14]
    DIRECTION INPUT ;
    USE SIGNAL ;
    SHAPE ABUTMENT ;
    PORT
      LAYER M4 ;
      RECT 0.000 30.192 0.024 30.216 ;
    END
  END wd_in_A[14]
  PIN wd_in_B[14]
    DIRECTION INPUT ;
    USE SIGNAL ;
    SHAPE ABUTMENT ;
    PORT
      LAYER M4 ;
      RECT 23.536 30.192 23.560 30.216 ;
    END
  END wd_in_B[14]
  PIN wd_in_A[15]
    DIRECTION INPUT ;
    USE SIGNAL ;
    SHAPE ABUTMENT ;
    PORT
      LAYER M4 ;
      RECT 0.000 30.576 0.024 30.600 ;
    END
  END wd_in_A[15]
  PIN wd_in_B[15]
    DIRECTION INPUT ;
    USE SIGNAL ;
    SHAPE ABUTMENT ;
    PORT
      LAYER M4 ;
      RECT 23.536 30.576 23.560 30.600 ;
    END
  END wd_in_B[15]
  PIN wd_in_A[16]
    DIRECTION INPUT ;
    USE SIGNAL ;
    SHAPE ABUTMENT ;
    PORT
      LAYER M4 ;
      RECT 0.000 30.960 0.024 30.984 ;
    END
  END wd_in_A[16]
  PIN wd_in_B[16]
    DIRECTION INPUT ;
    USE SIGNAL ;
    SHAPE ABUTMENT ;
    PORT
      LAYER M4 ;
      RECT 23.536 30.960 23.560 30.984 ;
    END
  END wd_in_B[16]
  PIN wd_in_A[17]
    DIRECTION INPUT ;
    USE SIGNAL ;
    SHAPE ABUTMENT ;
    PORT
      LAYER M4 ;
      RECT 0.000 31.344 0.024 31.368 ;
    END
  END wd_in_A[17]
  PIN wd_in_B[17]
    DIRECTION INPUT ;
    USE SIGNAL ;
    SHAPE ABUTMENT ;
    PORT
      LAYER M4 ;
      RECT 23.536 31.344 23.560 31.368 ;
    END
  END wd_in_B[17]
  PIN wd_in_A[18]
    DIRECTION INPUT ;
    USE SIGNAL ;
    SHAPE ABUTMENT ;
    PORT
      LAYER M4 ;
      RECT 0.000 31.728 0.024 31.752 ;
    END
  END wd_in_A[18]
  PIN wd_in_B[18]
    DIRECTION INPUT ;
    USE SIGNAL ;
    SHAPE ABUTMENT ;
    PORT
      LAYER M4 ;
      RECT 23.536 31.728 23.560 31.752 ;
    END
  END wd_in_B[18]
  PIN wd_in_A[19]
    DIRECTION INPUT ;
    USE SIGNAL ;
    SHAPE ABUTMENT ;
    PORT
      LAYER M4 ;
      RECT 0.000 32.112 0.024 32.136 ;
    END
  END wd_in_A[19]
  PIN wd_in_B[19]
    DIRECTION INPUT ;
    USE SIGNAL ;
    SHAPE ABUTMENT ;
    PORT
      LAYER M4 ;
      RECT 23.536 32.112 23.560 32.136 ;
    END
  END wd_in_B[19]
  PIN wd_in_A[20]
    DIRECTION INPUT ;
    USE SIGNAL ;
    SHAPE ABUTMENT ;
    PORT
      LAYER M4 ;
      RECT 0.000 32.496 0.024 32.520 ;
    END
  END wd_in_A[20]
  PIN wd_in_B[20]
    DIRECTION INPUT ;
    USE SIGNAL ;
    SHAPE ABUTMENT ;
    PORT
      LAYER M4 ;
      RECT 23.536 32.496 23.560 32.520 ;
    END
  END wd_in_B[20]
  PIN wd_in_A[21]
    DIRECTION INPUT ;
    USE SIGNAL ;
    SHAPE ABUTMENT ;
    PORT
      LAYER M4 ;
      RECT 0.000 32.880 0.024 32.904 ;
    END
  END wd_in_A[21]
  PIN wd_in_B[21]
    DIRECTION INPUT ;
    USE SIGNAL ;
    SHAPE ABUTMENT ;
    PORT
      LAYER M4 ;
      RECT 23.536 32.880 23.560 32.904 ;
    END
  END wd_in_B[21]
  PIN wd_in_A[22]
    DIRECTION INPUT ;
    USE SIGNAL ;
    SHAPE ABUTMENT ;
    PORT
      LAYER M4 ;
      RECT 0.000 33.264 0.024 33.288 ;
    END
  END wd_in_A[22]
  PIN wd_in_B[22]
    DIRECTION INPUT ;
    USE SIGNAL ;
    SHAPE ABUTMENT ;
    PORT
      LAYER M4 ;
      RECT 23.536 33.264 23.560 33.288 ;
    END
  END wd_in_B[22]
  PIN wd_in_A[23]
    DIRECTION INPUT ;
    USE SIGNAL ;
    SHAPE ABUTMENT ;
    PORT
      LAYER M4 ;
      RECT 0.000 33.648 0.024 33.672 ;
    END
  END wd_in_A[23]
  PIN wd_in_B[23]
    DIRECTION INPUT ;
    USE SIGNAL ;
    SHAPE ABUTMENT ;
    PORT
      LAYER M4 ;
      RECT 23.536 33.648 23.560 33.672 ;
    END
  END wd_in_B[23]
  PIN wd_in_A[24]
    DIRECTION INPUT ;
    USE SIGNAL ;
    SHAPE ABUTMENT ;
    PORT
      LAYER M4 ;
      RECT 0.000 34.032 0.024 34.056 ;
    END
  END wd_in_A[24]
  PIN wd_in_B[24]
    DIRECTION INPUT ;
    USE SIGNAL ;
    SHAPE ABUTMENT ;
    PORT
      LAYER M4 ;
      RECT 23.536 34.032 23.560 34.056 ;
    END
  END wd_in_B[24]
  PIN wd_in_A[25]
    DIRECTION INPUT ;
    USE SIGNAL ;
    SHAPE ABUTMENT ;
    PORT
      LAYER M4 ;
      RECT 0.000 34.416 0.024 34.440 ;
    END
  END wd_in_A[25]
  PIN wd_in_B[25]
    DIRECTION INPUT ;
    USE SIGNAL ;
    SHAPE ABUTMENT ;
    PORT
      LAYER M4 ;
      RECT 23.536 34.416 23.560 34.440 ;
    END
  END wd_in_B[25]
  PIN wd_in_A[26]
    DIRECTION INPUT ;
    USE SIGNAL ;
    SHAPE ABUTMENT ;
    PORT
      LAYER M4 ;
      RECT 0.000 34.800 0.024 34.824 ;
    END
  END wd_in_A[26]
  PIN wd_in_B[26]
    DIRECTION INPUT ;
    USE SIGNAL ;
    SHAPE ABUTMENT ;
    PORT
      LAYER M4 ;
      RECT 23.536 34.800 23.560 34.824 ;
    END
  END wd_in_B[26]
  PIN wd_in_A[27]
    DIRECTION INPUT ;
    USE SIGNAL ;
    SHAPE ABUTMENT ;
    PORT
      LAYER M4 ;
      RECT 0.000 35.184 0.024 35.208 ;
    END
  END wd_in_A[27]
  PIN wd_in_B[27]
    DIRECTION INPUT ;
    USE SIGNAL ;
    SHAPE ABUTMENT ;
    PORT
      LAYER M4 ;
      RECT 23.536 35.184 23.560 35.208 ;
    END
  END wd_in_B[27]
  PIN wd_in_A[28]
    DIRECTION INPUT ;
    USE SIGNAL ;
    SHAPE ABUTMENT ;
    PORT
      LAYER M4 ;
      RECT 0.000 35.568 0.024 35.592 ;
    END
  END wd_in_A[28]
  PIN wd_in_B[28]
    DIRECTION INPUT ;
    USE SIGNAL ;
    SHAPE ABUTMENT ;
    PORT
      LAYER M4 ;
      RECT 23.536 35.568 23.560 35.592 ;
    END
  END wd_in_B[28]
  PIN wd_in_A[29]
    DIRECTION INPUT ;
    USE SIGNAL ;
    SHAPE ABUTMENT ;
    PORT
      LAYER M4 ;
      RECT 0.000 35.952 0.024 35.976 ;
    END
  END wd_in_A[29]
  PIN wd_in_B[29]
    DIRECTION INPUT ;
    USE SIGNAL ;
    SHAPE ABUTMENT ;
    PORT
      LAYER M4 ;
      RECT 23.536 35.952 23.560 35.976 ;
    END
  END wd_in_B[29]
  PIN wd_in_A[30]
    DIRECTION INPUT ;
    USE SIGNAL ;
    SHAPE ABUTMENT ;
    PORT
      LAYER M4 ;
      RECT 0.000 36.336 0.024 36.360 ;
    END
  END wd_in_A[30]
  PIN wd_in_B[30]
    DIRECTION INPUT ;
    USE SIGNAL ;
    SHAPE ABUTMENT ;
    PORT
      LAYER M4 ;
      RECT 23.536 36.336 23.560 36.360 ;
    END
  END wd_in_B[30]
  PIN wd_in_A[31]
    DIRECTION INPUT ;
    USE SIGNAL ;
    SHAPE ABUTMENT ;
    PORT
      LAYER M4 ;
      RECT 0.000 36.720 0.024 36.744 ;
    END
  END wd_in_A[31]
  PIN wd_in_B[31]
    DIRECTION INPUT ;
    USE SIGNAL ;
    SHAPE ABUTMENT ;
    PORT
      LAYER M4 ;
      RECT 23.536 36.720 23.560 36.744 ;
    END
  END wd_in_B[31]
  PIN addr_in_A[0]
    DIRECTION INPUT ;
    USE SIGNAL ;
    SHAPE ABUTMENT ;
    PORT
      LAYER M4 ;
      RECT 0.000 37.200 0.024 37.224 ;
    END
  END addr_in_A[0]
  PIN addr_in_B[0]
    DIRECTION INPUT ;
    USE SIGNAL ;
    SHAPE ABUTMENT ;
    PORT
      LAYER M4 ;
      RECT 23.536 37.200 23.560 37.224 ;
    END
  END addr_in_B[0]
  PIN addr_in_A[1]
    DIRECTION INPUT ;
    USE SIGNAL ;
    SHAPE ABUTMENT ;
    PORT
      LAYER M4 ;
      RECT 0.000 37.584 0.024 37.608 ;
    END
  END addr_in_A[1]
  PIN addr_in_B[1]
    DIRECTION INPUT ;
    USE SIGNAL ;
    SHAPE ABUTMENT ;
    PORT
      LAYER M4 ;
      RECT 23.536 37.584 23.560 37.608 ;
    END
  END addr_in_B[1]
  PIN addr_in_A[2]
    DIRECTION INPUT ;
    USE SIGNAL ;
    SHAPE ABUTMENT ;
    PORT
      LAYER M4 ;
      RECT 0.000 37.968 0.024 37.992 ;
    END
  END addr_in_A[2]
  PIN addr_in_B[2]
    DIRECTION INPUT ;
    USE SIGNAL ;
    SHAPE ABUTMENT ;
    PORT
      LAYER M4 ;
      RECT 23.536 37.968 23.560 37.992 ;
    END
  END addr_in_B[2]
  PIN addr_in_A[3]
    DIRECTION INPUT ;
    USE SIGNAL ;
    SHAPE ABUTMENT ;
    PORT
      LAYER M4 ;
      RECT 0.000 38.352 0.024 38.376 ;
    END
  END addr_in_A[3]
  PIN addr_in_B[3]
    DIRECTION INPUT ;
    USE SIGNAL ;
    SHAPE ABUTMENT ;
    PORT
      LAYER M4 ;
      RECT 23.536 38.352 23.560 38.376 ;
    END
  END addr_in_B[3]
  PIN addr_in_A[4]
    DIRECTION INPUT ;
    USE SIGNAL ;
    SHAPE ABUTMENT ;
    PORT
      LAYER M4 ;
      RECT 0.000 38.736 0.024 38.760 ;
    END
  END addr_in_A[4]
  PIN addr_in_B[4]
    DIRECTION INPUT ;
    USE SIGNAL ;
    SHAPE ABUTMENT ;
    PORT
      LAYER M4 ;
      RECT 23.536 38.736 23.560 38.760 ;
    END
  END addr_in_B[4]
  PIN addr_in_A[5]
    DIRECTION INPUT ;
    USE SIGNAL ;
    SHAPE ABUTMENT ;
    PORT
      LAYER M4 ;
      RECT 0.000 39.120 0.024 39.144 ;
    END
  END addr_in_A[5]
  PIN addr_in_B[5]
    DIRECTION INPUT ;
    USE SIGNAL ;
    SHAPE ABUTMENT ;
    PORT
      LAYER M4 ;
      RECT 23.536 39.120 23.560 39.144 ;
    END
  END addr_in_B[5]
  PIN addr_in_A[6]
    DIRECTION INPUT ;
    USE SIGNAL ;
    SHAPE ABUTMENT ;
    PORT
      LAYER M4 ;
      RECT 0.000 39.504 0.024 39.528 ;
    END
  END addr_in_A[6]
  PIN addr_in_B[6]
    DIRECTION INPUT ;
    USE SIGNAL ;
    SHAPE ABUTMENT ;
    PORT
      LAYER M4 ;
      RECT 23.536 39.504 23.560 39.528 ;
    END
  END addr_in_B[6]
  PIN addr_in_A[7]
    DIRECTION INPUT ;
    USE SIGNAL ;
    SHAPE ABUTMENT ;
    PORT
      LAYER M4 ;
      RECT 0.000 39.888 0.024 39.912 ;
    END
  END addr_in_A[7]
  PIN addr_in_B[7]
    DIRECTION INPUT ;
    USE SIGNAL ;
    SHAPE ABUTMENT ;
    PORT
      LAYER M4 ;
      RECT 23.536 39.888 23.560 39.912 ;
    END
  END addr_in_B[7]
  PIN addr_in_A[8]
    DIRECTION INPUT ;
    USE SIGNAL ;
    SHAPE ABUTMENT ;
    PORT
      LAYER M4 ;
      RECT 0.000 40.272 0.024 40.296 ;
    END
  END addr_in_A[8]
  PIN addr_in_B[8]
    DIRECTION INPUT ;
    USE SIGNAL ;
    SHAPE ABUTMENT ;
    PORT
      LAYER M4 ;
      RECT 23.536 40.272 23.560 40.296 ;
    END
  END addr_in_B[8]
  PIN we_in_A
    DIRECTION INPUT ;
    USE SIGNAL ;
    SHAPE ABUTMENT ;
    PORT
      LAYER M4 ;
      RECT 0.000 40.752 0.024 40.776 ;
    END
  END we_in_A
  PIN we_in_B
    DIRECTION INPUT ;
    USE SIGNAL ;
    SHAPE ABUTMENT ;
    PORT
      LAYER M4 ;
      RECT 23.536 40.752 23.560 40.776 ;
    END
  END we_in_B
  PIN ce_in
    DIRECTION INPUT ;
    USE SIGNAL ;
    SHAPE ABUTMENT ;
    PORT
      LAYER M4 ;
      RECT 0.000 41.136 0.024 41.160 ;
    END
  END ce_in
  PIN clk
    DIRECTION INPUT ;
    USE SIGNAL ;
    SHAPE ABUTMENT ;
    PORT
      LAYER M4 ;
      RECT 0.000 41.520 0.024 41.544 ;
    END
  END clk
  PIN VSS
    DIRECTION INOUT ;
    USE GROUND ;
    PORT
      LAYER M4 ;
      RECT 0.048 0.000 23.512 0.096 ;
      RECT 0.048 0.768 23.512 0.864 ;
      RECT 0.048 1.536 23.512 1.632 ;
      RECT 0.048 2.304 23.512 2.400 ;
      RECT 0.048 3.072 23.512 3.168 ;
      RECT 0.048 3.840 23.512 3.936 ;
      RECT 0.048 4.608 23.512 4.704 ;
      RECT 0.048 5.376 23.512 5.472 ;
      RECT 0.048 6.144 23.512 6.240 ;
      RECT 0.048 6.912 23.512 7.008 ;
      RECT 0.048 7.680 23.512 7.776 ;
      RECT 0.048 8.448 23.512 8.544 ;
      RECT 0.048 9.216 23.512 9.312 ;
      RECT 0.048 9.984 23.512 10.080 ;
      RECT 0.048 10.752 23.512 10.848 ;
      RECT 0.048 11.520 23.512 11.616 ;
      RECT 0.048 12.288 23.512 12.384 ;
      RECT 0.048 13.056 23.512 13.152 ;
      RECT 0.048 13.824 23.512 13.920 ;
      RECT 0.048 14.592 23.512 14.688 ;
      RECT 0.048 15.360 23.512 15.456 ;
      RECT 0.048 16.128 23.512 16.224 ;
      RECT 0.048 16.896 23.512 16.992 ;
      RECT 0.048 17.664 23.512 17.760 ;
      RECT 0.048 18.432 23.512 18.528 ;
      RECT 0.048 19.200 23.512 19.296 ;
      RECT 0.048 19.968 23.512 20.064 ;
      RECT 0.048 20.736 23.512 20.832 ;
      RECT 0.048 21.504 23.512 21.600 ;
      RECT 0.048 22.272 23.512 22.368 ;
      RECT 0.048 23.040 23.512 23.136 ;
      RECT 0.048 23.808 23.512 23.904 ;
      RECT 0.048 24.576 23.512 24.672 ;
      RECT 0.048 25.344 23.512 25.440 ;
      RECT 0.048 26.112 23.512 26.208 ;
      RECT 0.048 26.880 23.512 26.976 ;
      RECT 0.048 27.648 23.512 27.744 ;
      RECT 0.048 28.416 23.512 28.512 ;
      RECT 0.048 29.184 23.512 29.280 ;
      RECT 0.048 29.952 23.512 30.048 ;
      RECT 0.048 30.720 23.512 30.816 ;
      RECT 0.048 31.488 23.512 31.584 ;
      RECT 0.048 32.256 23.512 32.352 ;
      RECT 0.048 33.024 23.512 33.120 ;
      RECT 0.048 33.792 23.512 33.888 ;
      RECT 0.048 34.560 23.512 34.656 ;
      RECT 0.048 35.328 23.512 35.424 ;
      RECT 0.048 36.096 23.512 36.192 ;
      RECT 0.048 36.864 23.512 36.960 ;
      RECT 0.048 37.632 23.512 37.728 ;
      RECT 0.048 38.400 23.512 38.496 ;
      RECT 0.048 39.168 23.512 39.264 ;
      RECT 0.048 39.936 23.512 40.032 ;
      RECT 0.048 40.704 23.512 40.800 ;
      RECT 0.048 41.472 23.512 41.568 ;
    END
  END VSS
  PIN VDD
    DIRECTION INOUT ;
    USE POWER ;
    PORT
      LAYER M4 ;
      RECT 0.048 0.384 23.512 0.480 ;
      RECT 0.048 1.152 23.512 1.248 ;
      RECT 0.048 1.920 23.512 2.016 ;
      RECT 0.048 2.688 23.512 2.784 ;
      RECT 0.048 3.456 23.512 3.552 ;
      RECT 0.048 4.224 23.512 4.320 ;
      RECT 0.048 4.992 23.512 5.088 ;
      RECT 0.048 5.760 23.512 5.856 ;
      RECT 0.048 6.528 23.512 6.624 ;
      RECT 0.048 7.296 23.512 7.392 ;
      RECT 0.048 8.064 23.512 8.160 ;
      RECT 0.048 8.832 23.512 8.928 ;
      RECT 0.048 9.600 23.512 9.696 ;
      RECT 0.048 10.368 23.512 10.464 ;
      RECT 0.048 11.136 23.512 11.232 ;
      RECT 0.048 11.904 23.512 12.000 ;
      RECT 0.048 12.672 23.512 12.768 ;
      RECT 0.048 13.440 23.512 13.536 ;
      RECT 0.048 14.208 23.512 14.304 ;
      RECT 0.048 14.976 23.512 15.072 ;
      RECT 0.048 15.744 23.512 15.840 ;
      RECT 0.048 16.512 23.512 16.608 ;
      RECT 0.048 17.280 23.512 17.376 ;
      RECT 0.048 18.048 23.512 18.144 ;
      RECT 0.048 18.816 23.512 18.912 ;
      RECT 0.048 19.584 23.512 19.680 ;
      RECT 0.048 20.352 23.512 20.448 ;
      RECT 0.048 21.120 23.512 21.216 ;
      RECT 0.048 21.888 23.512 21.984 ;
      RECT 0.048 22.656 23.512 22.752 ;
      RECT 0.048 23.424 23.512 23.520 ;
      RECT 0.048 24.192 23.512 24.288 ;
      RECT 0.048 24.960 23.512 25.056 ;
      RECT 0.048 25.728 23.512 25.824 ;
      RECT 0.048 26.496 23.512 26.592 ;
      RECT 0.048 27.264 23.512 27.360 ;
      RECT 0.048 28.032 23.512 28.128 ;
      RECT 0.048 28.800 23.512 28.896 ;
      RECT 0.048 29.568 23.512 29.664 ;
      RECT 0.048 30.336 23.512 30.432 ;
      RECT 0.048 31.104 23.512 31.200 ;
      RECT 0.048 31.872 23.512 31.968 ;
      RECT 0.048 32.640 23.512 32.736 ;
      RECT 0.048 33.408 23.512 33.504 ;
      RECT 0.048 34.176 23.512 34.272 ;
      RECT 0.048 34.944 23.512 35.040 ;
      RECT 0.048 35.712 23.512 35.808 ;
      RECT 0.048 36.480 23.512 36.576 ;
      RECT 0.048 37.248 23.512 37.344 ;
      RECT 0.048 38.016 23.512 38.112 ;
      RECT 0.048 38.784 23.512 38.880 ;
      RECT 0.048 39.552 23.512 39.648 ;
      RECT 0.048 40.320 23.512 40.416 ;
      RECT 0.048 41.088 23.512 41.184 ;
      RECT 0.048 41.856 23.512 41.952 ;
    END
  END VDD
  OBS
    LAYER M1 ;
    RECT 0 0 23.560 42.000 ;
    LAYER M2 ;
    RECT 0 0 23.560 42.000 ;
    LAYER M3 ;
    RECT 0 0 23.560 42.000 ;
    LAYER M4 ;
    RECT 0 0 23.560 42.000 ;
  END
END fakeram7_dp_512x32

END LIBRARY
